One B-rep face of a CAD part: STEP entity #25147.
In plain terms, the planar face has unit normal (0, 1, 0).
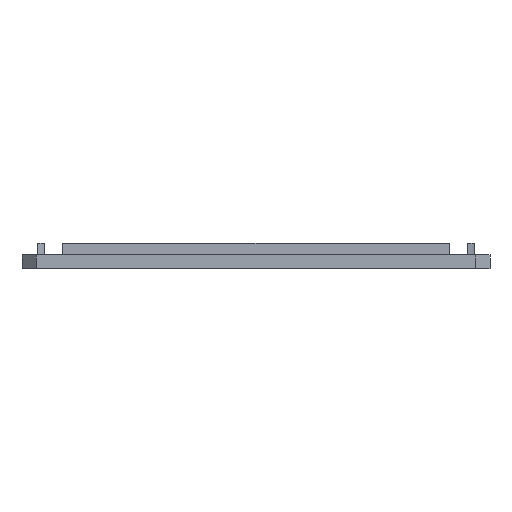
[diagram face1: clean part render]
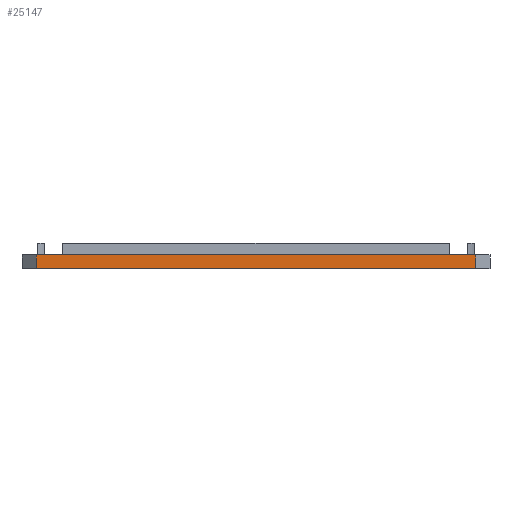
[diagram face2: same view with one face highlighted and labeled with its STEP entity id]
Its self-contained STEP definition (entity closure, numbers rounded to 3 decimals):
#144 = PLANE('',#145);
#145 = AXIS2_PLACEMENT_3D('',#146,#147,#148);
#146 = CARTESIAN_POINT('',(0.,0.,28.));
#147 = DIRECTION('',(0.,0.,1.));
#148 = DIRECTION('',(1.,0.,-0.));
#693 = PLANE('',#694);
#694 = AXIS2_PLACEMENT_3D('',#695,#696,#697);
#695 = CARTESIAN_POINT('',(0.,0.,30.4)
  );
#696 = DIRECTION('',(0.,0.,1.));
#697 = DIRECTION('',(1.,0.,-0.));
#719 = PLANE('',#720);
#720 = AXIS2_PLACEMENT_3D('',#721,#722,#723);
#721 = CARTESIAN_POINT('',(41.,52.5,28.));
#722 = DIRECTION('',(-0.707,-0.707,0.));
#723 = DIRECTION('',(-0.707,0.707,0.));
#24885 = VERTEX_POINT('',#24886);
#24886 = CARTESIAN_POINT('',(-38.5,55.,30.4));
#24902 = PLANE('',#24903);
#24903 = AXIS2_PLACEMENT_3D('',#24904,#24905,#24906);
#24904 = CARTESIAN_POINT('',(-38.5,55.,28.));
#24905 = DIRECTION('',(0.707,-0.707,0.));
#24906 = DIRECTION('',(-0.707,-0.707,0.));
#24938 = VERTEX_POINT('',#24939);
#24939 = CARTESIAN_POINT('',(38.5,55.,30.4));
#24960 = EDGE_CURVE('',#24938,#24885,#24961,.T.);
#24961 = SURFACE_CURVE('',#24962,(#24966,#24973),.PCURVE_S1.);
#24962 = LINE('',#24963,#24964);
#24963 = CARTESIAN_POINT('',(38.5,55.,30.4));
#24964 = VECTOR('',#24965,1.);
#24965 = DIRECTION('',(-1.,0.,0.));
#24966 = PCURVE('',#693,#24967);
#24967 = DEFINITIONAL_REPRESENTATION('',(#24968),#24972);
#24968 = LINE('',#24969,#24970);
#24969 = CARTESIAN_POINT('',(38.5,55.));
#24970 = VECTOR('',#24971,1.);
#24971 = DIRECTION('',(-1.,0.));
#24972 = ( GEOMETRIC_REPRESENTATION_CONTEXT(2) 
PARAMETRIC_REPRESENTATION_CONTEXT() REPRESENTATION_CONTEXT('2D SPACE',''
  ) );
#24973 = PCURVE('',#24974,#24979);
#24974 = PLANE('',#24975);
#24975 = AXIS2_PLACEMENT_3D('',#24976,#24977,#24978);
#24976 = CARTESIAN_POINT('',(38.5,55.,28.));
#24977 = DIRECTION('',(0.,-1.,0.));
#24978 = DIRECTION('',(-1.,0.,0.));
#24979 = DEFINITIONAL_REPRESENTATION('',(#24980),#24984);
#24980 = LINE('',#24981,#24982);
#24981 = CARTESIAN_POINT('',(0.,-2.4));
#24982 = VECTOR('',#24983,1.);
#24983 = DIRECTION('',(1.,0.));
#24984 = ( GEOMETRIC_REPRESENTATION_CONTEXT(2) 
PARAMETRIC_REPRESENTATION_CONTEXT() REPRESENTATION_CONTEXT('2D SPACE',''
  ) );
#25147 = ADVANCED_FACE('',(#25148),#24974,.F.);
#25148 = FACE_BOUND('',#25149,.F.);
#25149 = EDGE_LOOP('',(#25150,#25173,#25174,#25197));
#25150 = ORIENTED_EDGE('',*,*,#25151,.T.);
#25151 = EDGE_CURVE('',#25152,#24938,#25154,.T.);
#25152 = VERTEX_POINT('',#25153);
#25153 = CARTESIAN_POINT('',(38.5,55.,28.));
#25154 = SURFACE_CURVE('',#25155,(#25159,#25166),.PCURVE_S1.);
#25155 = LINE('',#25156,#25157);
#25156 = CARTESIAN_POINT('',(38.5,55.,28.));
#25157 = VECTOR('',#25158,1.);
#25158 = DIRECTION('',(0.,0.,1.));
#25159 = PCURVE('',#24974,#25160);
#25160 = DEFINITIONAL_REPRESENTATION('',(#25161),#25165);
#25161 = LINE('',#25162,#25163);
#25162 = CARTESIAN_POINT('',(0.,-0.));
#25163 = VECTOR('',#25164,1.);
#25164 = DIRECTION('',(0.,-1.));
#25165 = ( GEOMETRIC_REPRESENTATION_CONTEXT(2) 
PARAMETRIC_REPRESENTATION_CONTEXT() REPRESENTATION_CONTEXT('2D SPACE',''
  ) );
#25166 = PCURVE('',#719,#25167);
#25167 = DEFINITIONAL_REPRESENTATION('',(#25168),#25172);
#25168 = LINE('',#25169,#25170);
#25169 = CARTESIAN_POINT('',(3.536,0.));
#25170 = VECTOR('',#25171,1.);
#25171 = DIRECTION('',(0.,-1.));
#25172 = ( GEOMETRIC_REPRESENTATION_CONTEXT(2) 
PARAMETRIC_REPRESENTATION_CONTEXT() REPRESENTATION_CONTEXT('2D SPACE',''
  ) );
#25173 = ORIENTED_EDGE('',*,*,#24960,.T.);
#25174 = ORIENTED_EDGE('',*,*,#25175,.F.);
#25175 = EDGE_CURVE('',#25176,#24885,#25178,.T.);
#25176 = VERTEX_POINT('',#25177);
#25177 = CARTESIAN_POINT('',(-38.5,55.,28.));
#25178 = SURFACE_CURVE('',#25179,(#25183,#25190),.PCURVE_S1.);
#25179 = LINE('',#25180,#25181);
#25180 = CARTESIAN_POINT('',(-38.5,55.,28.));
#25181 = VECTOR('',#25182,1.);
#25182 = DIRECTION('',(0.,0.,1.));
#25183 = PCURVE('',#24974,#25184);
#25184 = DEFINITIONAL_REPRESENTATION('',(#25185),#25189);
#25185 = LINE('',#25186,#25187);
#25186 = CARTESIAN_POINT('',(77.,0.));
#25187 = VECTOR('',#25188,1.);
#25188 = DIRECTION('',(0.,-1.));
#25189 = ( GEOMETRIC_REPRESENTATION_CONTEXT(2) 
PARAMETRIC_REPRESENTATION_CONTEXT() REPRESENTATION_CONTEXT('2D SPACE',''
  ) );
#25190 = PCURVE('',#24902,#25191);
#25191 = DEFINITIONAL_REPRESENTATION('',(#25192),#25196);
#25192 = LINE('',#25193,#25194);
#25193 = CARTESIAN_POINT('',(0.,0.));
#25194 = VECTOR('',#25195,1.);
#25195 = DIRECTION('',(0.,-1.));
#25196 = ( GEOMETRIC_REPRESENTATION_CONTEXT(2) 
PARAMETRIC_REPRESENTATION_CONTEXT() REPRESENTATION_CONTEXT('2D SPACE',''
  ) );
#25197 = ORIENTED_EDGE('',*,*,#25198,.F.);
#25198 = EDGE_CURVE('',#25152,#25176,#25199,.T.);
#25199 = SURFACE_CURVE('',#25200,(#25204,#25211),.PCURVE_S1.);
#25200 = LINE('',#25201,#25202);
#25201 = CARTESIAN_POINT('',(38.5,55.,28.));
#25202 = VECTOR('',#25203,1.);
#25203 = DIRECTION('',(-1.,0.,0.));
#25204 = PCURVE('',#24974,#25205);
#25205 = DEFINITIONAL_REPRESENTATION('',(#25206),#25210);
#25206 = LINE('',#25207,#25208);
#25207 = CARTESIAN_POINT('',(0.,-0.));
#25208 = VECTOR('',#25209,1.);
#25209 = DIRECTION('',(1.,0.));
#25210 = ( GEOMETRIC_REPRESENTATION_CONTEXT(2) 
PARAMETRIC_REPRESENTATION_CONTEXT() REPRESENTATION_CONTEXT('2D SPACE',''
  ) );
#25211 = PCURVE('',#144,#25212);
#25212 = DEFINITIONAL_REPRESENTATION('',(#25213),#25217);
#25213 = LINE('',#25214,#25215);
#25214 = CARTESIAN_POINT('',(38.5,55.));
#25215 = VECTOR('',#25216,1.);
#25216 = DIRECTION('',(-1.,0.));
#25217 = ( GEOMETRIC_REPRESENTATION_CONTEXT(2) 
PARAMETRIC_REPRESENTATION_CONTEXT() REPRESENTATION_CONTEXT('2D SPACE',''
  ) );
